VERSION 5.7 ;
  NOWIREEXTENSIONATPIN ON ;
  DIVIDERCHAR "/" ;
  BUSBITCHARS "[]" ;
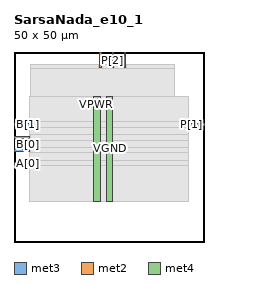
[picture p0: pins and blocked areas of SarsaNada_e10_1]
MACRO SarsaNada_e10_1
  CLASS BLOCK ;
  FOREIGN SarsaNada_e10_1 ;
  ORIGIN 0.000 0.000 ;
  SIZE 50.000 BY 50.000 ;
  PIN A[0]
    DIRECTION INPUT ;
    USE SIGNAL ;
    ANTENNAGATEAREA 0.196500 ;
    PORT
      LAYER met3 ;
        RECT 0.000 20.440 4.000 21.040 ;
    END
  END A[0]
  PIN A[1]
    DIRECTION INPUT ;
    USE SIGNAL ;
    ANTENNAGATEAREA 0.196500 ;
    PORT
      LAYER met2 ;
        RECT 29.070 46.000 29.350 50.000 ;
    END
  END A[1]
  PIN B[0]
    DIRECTION INPUT ;
    USE SIGNAL ;
    ANTENNAGATEAREA 0.196500 ;
    PORT
      LAYER met3 ;
        RECT 0.000 27.240 4.000 27.840 ;
    END
  END B[0]
  PIN B[1]
    DIRECTION INPUT ;
    USE SIGNAL ;
    ANTENNAGATEAREA 0.196500 ;
    PORT
      LAYER met3 ;
        RECT 0.000 30.640 4.000 31.240 ;
    END
  END B[1]
  PIN P[0]
    DIRECTION OUTPUT ;
    USE SIGNAL ;
    ANTENNADIFFAREA 0.445500 ;
    PORT
      LAYER met3 ;
        RECT 0.000 23.840 4.000 24.440 ;
    END
  END P[0]
  PIN P[1]
    DIRECTION OUTPUT ;
    USE SIGNAL ;
    ANTENNADIFFAREA 0.445500 ;
    PORT
      LAYER met3 ;
        RECT 46.000 30.640 50.000 31.240 ;
    END
  END P[1]
  PIN P[2]
    DIRECTION OUTPUT ;
    USE SIGNAL ;
    ANTENNADIFFAREA 0.445500 ;
    PORT
      LAYER met2 ;
        RECT 25.850 46.000 26.130 50.000 ;
    END
  END P[2]
  PIN P[3]
    DIRECTION OUTPUT ;
    USE SIGNAL ;
    ANTENNADIFFAREA 0.445500 ;
    PORT
      LAYER met2 ;
        RECT 22.630 46.000 22.910 50.000 ;
    END
  END P[3]
  PIN VGND
    DIRECTION INOUT ;
    USE GROUND ;
    PORT
      LAYER met4 ;
        RECT 24.340 10.640 25.940 38.320 ;
    END
  END VGND
  PIN VPWR
    DIRECTION INOUT ;
    USE POWER ;
    PORT
      LAYER met4 ;
        RECT 21.040 10.640 22.640 38.320 ;
    END
  END VPWR
  OBS
      LAYER nwell ;
        RECT 5.330 10.795 44.350 38.165 ;
      LAYER li1 ;
        RECT 5.520 10.795 44.160 38.165 ;
      LAYER met1 ;
        RECT 4.210 10.640 44.160 38.320 ;
      LAYER met2 ;
        RECT 4.230 45.720 22.350 46.650 ;
        RECT 23.190 45.720 25.570 46.650 ;
        RECT 26.410 45.720 28.790 46.650 ;
        RECT 29.630 45.720 42.230 46.650 ;
        RECT 4.230 10.695 42.230 45.720 ;
      LAYER met3 ;
        RECT 3.990 31.640 46.000 38.245 ;
        RECT 4.400 30.240 45.600 31.640 ;
        RECT 3.990 28.240 46.000 30.240 ;
        RECT 4.400 26.840 46.000 28.240 ;
        RECT 3.990 24.840 46.000 26.840 ;
        RECT 4.400 23.440 46.000 24.840 ;
        RECT 3.990 21.440 46.000 23.440 ;
        RECT 4.400 20.040 46.000 21.440 ;
        RECT 3.990 10.715 46.000 20.040 ;
  END
END SarsaNada_e10_1
END LIBRARY

